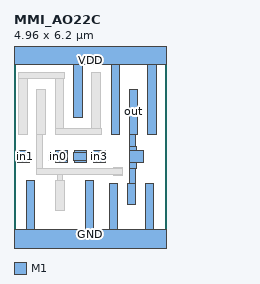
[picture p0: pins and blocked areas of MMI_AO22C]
MACRO MMI_AO22C
	CLASS CORE ;
	FOREIGN MMI_AO22C 0 0 ;
	SIZE 4.96 BY 6.2 ;
	SYMMETRY X Y ;
	SITE CORE1 ;
	PIN out
		DIRECTION output ;
		USE SIGNAL ;
		PORT
			LAYER M1 ;
			RECT 3.765 3.515 4.045 4.985 ;
			LAYER M1 ;
			RECT 3.78 3.13 3.97 3.515 ;
			LAYER M1 ;
			RECT 3.78 2.98 3.985 3.13 ;
			LAYER M1 ;
			RECT 3.78 2.6 4.22 2.98 ;
			LAYER M1 ;
			RECT 3.78 2.39 3.985 2.6 ;
			LAYER M1 ;
			RECT 3.78 1.91 3.97 2.39 ;
			LAYER M1 ;
			RECT 3.695 1.21 3.975 1.91 ;
		END
		AntennaDiffArea 1.0164 ;
	END out
	PIN in1
		DIRECTION input ;
		USE SIGNAL ;
		PORT
			LAYER M1 ;
			RECT 0.12 2.6 0.5 2.98 ;
		END
		AntennaGateArea 0.468 ;
	END in1
	PIN GND
		DIRECTION inout ;
		USE GROUND ;
		PORT
			LAYER M1 ;
			RECT 0.395 0.42 0.675 2.01 ;
			LAYER M1 ;
			RECT 2.325 0.42 2.605 2.01 ;
			LAYER M1 ;
			RECT 3.105 0.42 3.385 1.91 ;
			LAYER M1 ;
			RECT 4.285 0.42 4.565 1.91 ;
			LAYER M1 ;
			RECT 0 -0.42 4.96 0.42 ;
		END
	END GND
	PIN in2
		DIRECTION input ;
		USE SIGNAL ;
		PORT
			LAYER M1 ;
			RECT 1.98 2.93 2.36 2.98 ;
			LAYER M1 ;
			RECT 1.94 2.65 2.36 2.93 ;
			LAYER M1 ;
			RECT 1.98 2.6 2.36 2.65 ;
		END
		AntennaGateArea 0.468 ;
	END in2
	PIN VDD
		DIRECTION inout ;
		USE POWER ;
		PORT
			LAYER M1 ;
			RECT 0 5.78 4.96 6.62 ;
			LAYER M1 ;
			RECT 1.955 4.075 2.235 5.78 ;
			LAYER M1 ;
			RECT 3.175 3.515 3.455 5.78 ;
			LAYER M1 ;
			RECT 4.355 3.515 4.635 5.78 ;
		END
	END VDD
	PIN in3
		DIRECTION input ;
		USE SIGNAL ;
		PORT
			LAYER M1 ;
			RECT 2.6 2.935 2.98 2.98 ;
			LAYER M1 ;
			RECT 2.57 2.655 2.98 2.935 ;
			LAYER M1 ;
			RECT 2.6 2.6 2.98 2.655 ;
		END
		AntennaGateArea 0.468 ;
	END in3
	PIN in0
		DIRECTION input ;
		USE SIGNAL ;
		PORT
			LAYER M1 ;
			RECT 1.36 2.93 1.74 2.98 ;
			LAYER M1 ;
			RECT 1.14 2.65 1.74 2.93 ;
			LAYER M1 ;
			RECT 1.36 2.6 1.74 2.65 ;
		END
		AntennaGateArea 0.468 ;
	END in0
	OBS
		LAYER M1 ;
		RECT 0.16 5.52 0.44 5.525 ;
		LAYER M1 ;
		RECT 1.34 5.52 1.62 5.525 ;
		LAYER M1 ;
		RECT 0.15 5.33 1.64 5.52 ;
		LAYER M1 ;
		RECT 0.16 3.515 0.44 5.33 ;
		LAYER M1 ;
		RECT 0.75 3.515 1.03 4.965 ;
		LAYER M1 ;
		RECT 1.34 3.705 1.62 5.33 ;
		LAYER M1 ;
		RECT 2.545 3.705 2.825 5.525 ;
		LAYER M1 ;
		RECT 1.34 3.515 2.85 3.705 ;
		LAYER M1 ;
		RECT 0.75 2.4 0.94 3.515 ;
		LAYER M1 ;
		RECT 1.36 3.51 2.85 3.515 ;
		LAYER M1 ;
		RECT 3.25 2.4 3.53 2.435 ;
		LAYER M1 ;
		RECT 0.75 2.21 3.53 2.4 ;
		LAYER M1 ;
		RECT 1.405 2.01 1.595 2.21 ;
		LAYER M1 ;
		RECT 3.25 2.155 3.53 2.21 ;
		LAYER M1 ;
		RECT 1.365 1.04 1.645 2.01 ;
	END
END MMI_AO22C
